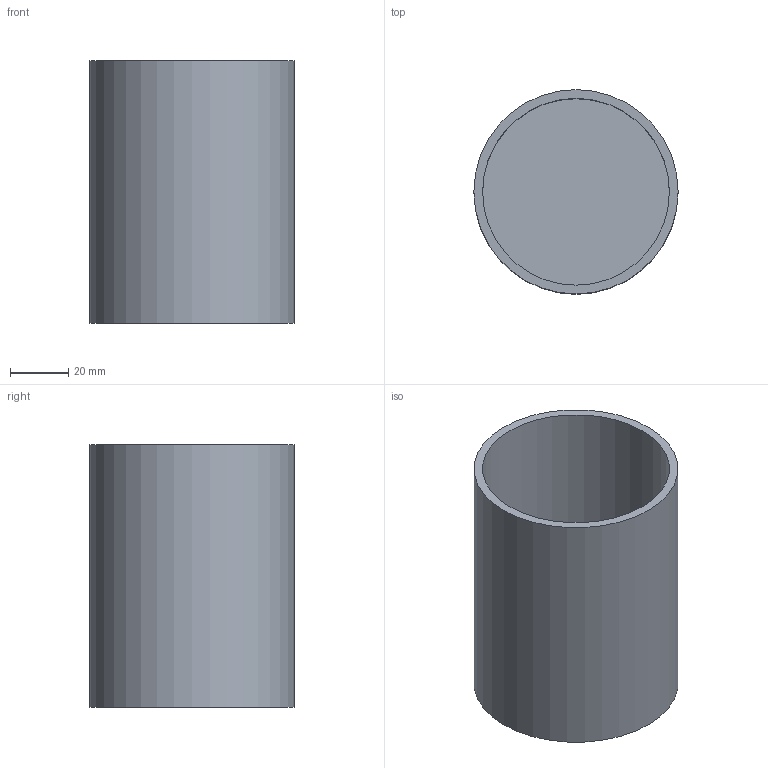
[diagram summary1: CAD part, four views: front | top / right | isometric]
STEP (ISO 10303-21) file: header records copied from the file, then geometry measured from it (millimetres).
FILE_DESCRIPTION(('Open CASCADE Model'),'2;1');
FILE_NAME('Open CASCADE Shape Model','2026-10-21T16:53:53',('Author'),( 'Open CASCADE'),'Open CASCADE STEP processor 7.9','Open CASCADE 7.9' ,'Unknown');
FILE_SCHEMA(('AUTOMOTIVE_DESIGN { 1 0 10303 214 1 1 1 1 }'));
Length unit declared in the file: millimetre
Products named in the file (1): Open CASCADE STEP translator 7.9 23
Bounding box: 70 x 70 x 90 mm (x, y, z)
Volume: 76876.6 mm3; surface area: 44926 mm2
Topology: 1 solids, 1 shells, 17 faces, 24 edges, 16 vertices
Faces by surface type: plane 9, cylinder 8
Full cylindrical faces by diameter (mm): 2.5 x4, 46 x1, 58 x1, 64 x1, 70 x1
Entity records: 717 total; most frequent: CARTESIAN_POINT 148, DIRECTION 117, ORIENTED_EDGE 48, PCURVE 48, DEFINITIONAL_REPRESENTATION 48, LINE 40, VECTOR 40, AXIS2_PLACEMENT_3D 34
One B-rep face of a CAD part: STEP entity #17.
In plain terms, the cylindrical face has radius 35 mm (diameter 70 mm), a full revolution.
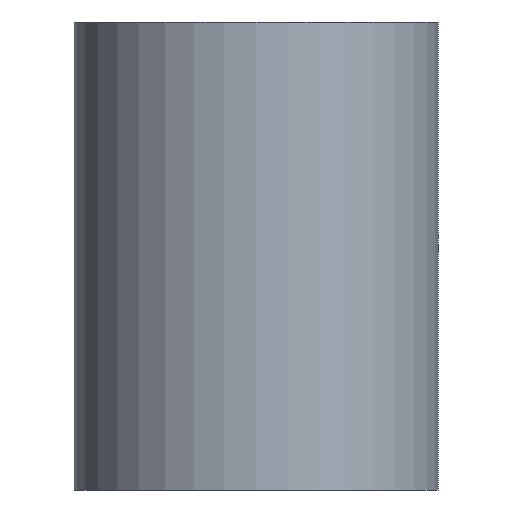
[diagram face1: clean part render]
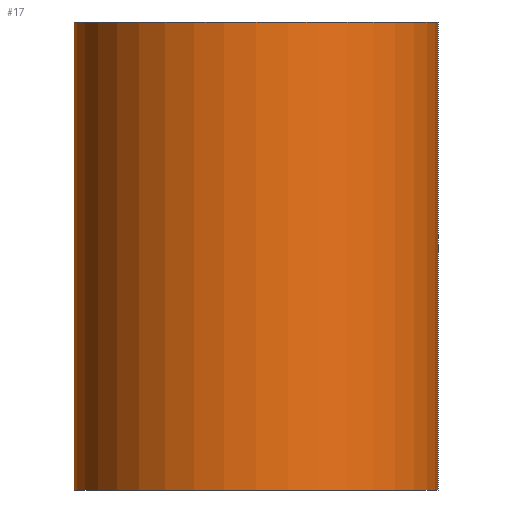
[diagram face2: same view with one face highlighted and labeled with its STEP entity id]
Its self-contained STEP definition (entity closure, numbers rounded to 3 decimals):
#17 = ADVANCED_FACE('',(#18),#32,.T.);
#18 = FACE_BOUND('',#19,.F.);
#19 = EDGE_LOOP('',(#20,#50,#77,#78));
#20 = ORIENTED_EDGE('',*,*,#21,.T.);
#21 = EDGE_CURVE('',#22,#24,#26,.T.);
#22 = VERTEX_POINT('',#23);
#23 = CARTESIAN_POINT('',(35.,0.,0.));
#24 = VERTEX_POINT('',#25);
#25 = CARTESIAN_POINT('',(35.,0.,90.));
#26 = SEAM_CURVE('',#27,(#31,#43),.PCURVE_S1.);
#27 = LINE('',#28,#29);
#28 = CARTESIAN_POINT('',(35.,0.,0.));
#29 = VECTOR('',#30,1.);
#30 = DIRECTION('',(0.,0.,1.));
#31 = PCURVE('',#32,#37);
#32 = CYLINDRICAL_SURFACE('',#33,35.);
#33 = AXIS2_PLACEMENT_3D('',#34,#35,#36);
#34 = CARTESIAN_POINT('',(0.,0.,0.));
#35 = DIRECTION('',(-0.,-0.,-1.));
#36 = DIRECTION('',(1.,0.,0.));
#37 = DEFINITIONAL_REPRESENTATION('',(#38),#42);
#38 = LINE('',#39,#40);
#39 = CARTESIAN_POINT('',(-0.,0.));
#40 = VECTOR('',#41,1.);
#41 = DIRECTION('',(-0.,-1.));
#42 = ( GEOMETRIC_REPRESENTATION_CONTEXT(2) 
PARAMETRIC_REPRESENTATION_CONTEXT() REPRESENTATION_CONTEXT('2D SPACE',''
  ) );
#43 = PCURVE('',#32,#44);
#44 = DEFINITIONAL_REPRESENTATION('',(#45),#49);
#45 = LINE('',#46,#47);
#46 = CARTESIAN_POINT('',(-6.283,0.));
#47 = VECTOR('',#48,1.);
#48 = DIRECTION('',(-0.,-1.));
#49 = ( GEOMETRIC_REPRESENTATION_CONTEXT(2) 
PARAMETRIC_REPRESENTATION_CONTEXT() REPRESENTATION_CONTEXT('2D SPACE',''
  ) );
#50 = ORIENTED_EDGE('',*,*,#51,.T.);
#51 = EDGE_CURVE('',#24,#24,#52,.T.);
#52 = SURFACE_CURVE('',#53,(#58,#65),.PCURVE_S1.);
#53 = CIRCLE('',#54,35.);
#54 = AXIS2_PLACEMENT_3D('',#55,#56,#57);
#55 = CARTESIAN_POINT('',(0.,0.,90.));
#56 = DIRECTION('',(0.,0.,1.));
#57 = DIRECTION('',(1.,0.,0.));
#58 = PCURVE('',#32,#59);
#59 = DEFINITIONAL_REPRESENTATION('',(#60),#64);
#60 = LINE('',#61,#62);
#61 = CARTESIAN_POINT('',(-0.,-90.));
#62 = VECTOR('',#63,1.);
#63 = DIRECTION('',(-1.,0.));
#64 = ( GEOMETRIC_REPRESENTATION_CONTEXT(2) 
PARAMETRIC_REPRESENTATION_CONTEXT() REPRESENTATION_CONTEXT('2D SPACE',''
  ) );
#65 = PCURVE('',#66,#71);
#66 = PLANE('',#67);
#67 = AXIS2_PLACEMENT_3D('',#68,#69,#70);
#68 = CARTESIAN_POINT('',(0.,0.,90.));
#69 = DIRECTION('',(0.,0.,1.));
#70 = DIRECTION('',(1.,0.,-0.));
#71 = DEFINITIONAL_REPRESENTATION('',(#72),#76);
#72 = CIRCLE('',#73,35.);
#73 = AXIS2_PLACEMENT_2D('',#74,#75);
#74 = CARTESIAN_POINT('',(0.,0.));
#75 = DIRECTION('',(1.,0.));
#76 = ( GEOMETRIC_REPRESENTATION_CONTEXT(2) 
PARAMETRIC_REPRESENTATION_CONTEXT() REPRESENTATION_CONTEXT('2D SPACE',''
  ) );
#77 = ORIENTED_EDGE('',*,*,#21,.F.);
#78 = ORIENTED_EDGE('',*,*,#79,.F.);
#79 = EDGE_CURVE('',#22,#22,#80,.T.);
#80 = SURFACE_CURVE('',#81,(#86,#93),.PCURVE_S1.);
#81 = CIRCLE('',#82,35.);
#82 = AXIS2_PLACEMENT_3D('',#83,#84,#85);
#83 = CARTESIAN_POINT('',(0.,0.,0.));
#84 = DIRECTION('',(0.,0.,1.));
#85 = DIRECTION('',(1.,0.,0.));
#86 = PCURVE('',#32,#87);
#87 = DEFINITIONAL_REPRESENTATION('',(#88),#92);
#88 = LINE('',#89,#90);
#89 = CARTESIAN_POINT('',(-0.,0.));
#90 = VECTOR('',#91,1.);
#91 = DIRECTION('',(-1.,0.));
#92 = ( GEOMETRIC_REPRESENTATION_CONTEXT(2) 
PARAMETRIC_REPRESENTATION_CONTEXT() REPRESENTATION_CONTEXT('2D SPACE',''
  ) );
#93 = PCURVE('',#94,#99);
#94 = PLANE('',#95);
#95 = AXIS2_PLACEMENT_3D('',#96,#97,#98);
#96 = CARTESIAN_POINT('',(0.,0.,0.));
#97 = DIRECTION('',(0.,0.,1.));
#98 = DIRECTION('',(1.,0.,-0.));
#99 = DEFINITIONAL_REPRESENTATION('',(#100),#104);
#100 = CIRCLE('',#101,35.);
#101 = AXIS2_PLACEMENT_2D('',#102,#103);
#102 = CARTESIAN_POINT('',(0.,0.));
#103 = DIRECTION('',(1.,0.));
#104 = ( GEOMETRIC_REPRESENTATION_CONTEXT(2) 
PARAMETRIC_REPRESENTATION_CONTEXT() REPRESENTATION_CONTEXT('2D SPACE',''
  ) );
